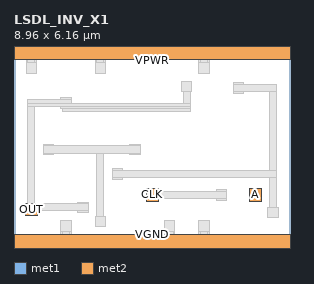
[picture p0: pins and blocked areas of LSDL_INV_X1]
MACRO LSDL_INV_X1
 CLASS CORE ;
 FOREIGN LSDL_INV_X1 0 0 ;
 SIZE 8.96 BY 6.16 ;
 ORIGIN 0 0 ;
 SYMMETRY X Y R90 ;
 SITE unit ;
  PIN VPWR
   DIRECTION INOUT ;
   USE POWER ;
   SHAPE ABUTMENT ;
    PORT
     CLASS CORE ;
       LAYER met1 ;
        RECT 0.00000000 5.92000000 8.96000000 6.40000000 ;
       LAYER met2 ;
        RECT 0.00000000 5.92000000 8.96000000 6.40000000 ;
    END
  END VPWR

  PIN VGND
   DIRECTION INOUT ;
   USE POWER ;
   SHAPE ABUTMENT ;
    PORT
     CLASS CORE ;
       LAYER met1 ;
        RECT 0.00000000 -0.24000000 8.96000000 0.24000000 ;
       LAYER met2 ;
        RECT 0.00000000 -0.24000000 8.96000000 0.24000000 ;
    END
  END VGND

  PIN OUT
   DIRECTION INOUT ;
   USE SIGNAL ;
   SHAPE ABUTMENT ;
    PORT
     CLASS CORE ;
       LAYER met2 ;
        RECT 0.36000000 0.86000000 0.76000000 1.26000000 ;
    END
  END OUT

  PIN CLK
   DIRECTION INOUT ;
   USE SIGNAL ;
   SHAPE ABUTMENT ;
    PORT
     CLASS CORE ;
       LAYER met2 ;
        RECT 4.28000000 1.32700000 4.68000000 1.72700000 ;
    END
  END CLK

  PIN A
   DIRECTION INOUT ;
   USE SIGNAL ;
   SHAPE ABUTMENT ;
    PORT
     CLASS CORE ;
       LAYER met2 ;
        RECT 7.64000000 1.32700000 8.04000000 1.72700000 ;
    END
  END A

 OBS
    LAYER polycont ;
     RECT 4.37000000 1.41700000 4.59000000 1.63700000 ;
     RECT 6.61000000 1.41700000 6.83000000 1.63700000 ;
     RECT 2.13000000 1.01200000 2.35000000 1.23200000 ;
     RECT 5.49000000 4.92700000 5.71000000 5.14700000 ;
     RECT 3.25000000 2.09200000 3.47000000 2.31200000 ;
     RECT 7.73000000 1.41700000 7.95000000 1.63700000 ;
     RECT 1.01000000 2.89000000 1.23000000 3.11000000 ;

    LAYER pdiffc ;
     RECT 1.57000000 4.39000000 1.79000000 4.61000000 ;
     RECT 0.45000000 5.53000000 0.67000000 5.75000000 ;
     RECT 2.69000000 5.53000000 2.91000000 5.75000000 ;
     RECT 6.05000000 5.53000000 6.27000000 5.75000000 ;
     RECT 7.17000000 4.89000000 7.39000000 5.11000000 ;
     RECT 3.81000000 2.89000000 4.03000000 3.11000000 ;

    LAYER ndiffc ;
     RECT 0.45000000 0.95000000 0.67000000 1.17000000 ;
     RECT 8.29000000 0.85000000 8.51000000 1.07000000 ;
     RECT 1.57000000 0.41000000 1.79000000 0.63000000 ;
     RECT 4.93000000 0.41000000 5.15000000 0.63000000 ;
     RECT 6.05000000 0.41000000 6.27000000 0.63000000 ;
     RECT 2.69000000 0.55000000 2.91000000 0.77000000 ;

    LAYER met1 ;
     RECT 1.51000000 0.24000000 1.56500000 0.35000000 ;
     RECT 1.79500000 0.24000000 1.85000000 0.35000000 ;
     RECT 4.87000000 0.24000000 4.92500000 0.35000000 ;
     RECT 5.15500000 0.24000000 5.21000000 0.35000000 ;
     RECT 5.99000000 0.24000000 6.04500000 0.35000000 ;
     RECT 6.27500000 0.24000000 6.33000000 0.35000000 ;
     RECT 0.39000000 5.81000000 0.44500000 5.92000000 ;
     RECT 0.67500000 5.81000000 0.73000000 5.92000000 ;
     RECT 2.63000000 5.81000000 2.68500000 5.92000000 ;
     RECT 2.91500000 5.81000000 2.97000000 5.92000000 ;
     RECT 5.99000000 5.81000000 6.04500000 5.92000000 ;
     RECT 6.27500000 5.81000000 6.33000000 5.92000000 ;
     RECT 4.28000000 1.32700000 4.68000000 1.41200000 ;
     RECT 6.55000000 1.35700000 6.89000000 1.41200000 ;
     RECT 4.28000000 1.41200000 6.89000000 1.64200000 ;
     RECT 6.55000000 1.64200000 6.89000000 1.69700000 ;
     RECT 4.28000000 1.64200000 4.68000000 1.72700000 ;
     RECT 0.36000000 0.86000000 0.76000000 1.00700000 ;
     RECT 2.07000000 0.95200000 2.41000000 1.00700000 ;
     RECT 0.36000000 1.00700000 2.41000000 1.23700000 ;
     RECT 0.36000000 1.23700000 0.76000000 1.26000000 ;
     RECT 2.07000000 1.23700000 2.41000000 1.29200000 ;
     RECT 1.56500000 4.24700000 5.71500000 4.33000000 ;
     RECT 0.44500000 1.26000000 0.67500000 4.38500000 ;
     RECT 1.51000000 4.33000000 5.71500000 4.38500000 ;
     RECT 0.44500000 4.38500000 5.71500000 4.47700000 ;
     RECT 0.44500000 4.47700000 1.85000000 4.61500000 ;
     RECT 1.51000000 4.61500000 1.85000000 4.67000000 ;
     RECT 5.48500000 4.47700000 5.71500000 4.86700000 ;
     RECT 5.43000000 4.86700000 5.77000000 5.20700000 ;
     RECT 0.39000000 5.47000000 0.73000000 5.81000000 ;
     RECT 2.63000000 5.47000000 2.97000000 5.81000000 ;
     RECT 5.99000000 5.47000000 6.33000000 5.81000000 ;
     RECT 0.44500000 5.81000000 0.67500000 5.92000000 ;
     RECT 2.68500000 5.81000000 2.91500000 5.92000000 ;
     RECT 6.04500000 5.81000000 6.27500000 5.92000000 ;
     RECT 0.00000000 5.92000000 8.96000000 6.40000000 ;
     RECT 8.23000000 0.79000000 8.57000000 1.13000000 ;
     RECT 3.19000000 2.03200000 3.53000000 2.08700000 ;
     RECT 8.28500000 1.13000000 8.51500000 2.08700000 ;
     RECT 3.19000000 2.08700000 8.51500000 2.31700000 ;
     RECT 3.19000000 2.31700000 3.53000000 2.37200000 ;
     RECT 7.11000000 4.83000000 7.45000000 4.88500000 ;
     RECT 8.28500000 2.31700000 8.51500000 4.88500000 ;
     RECT 7.11000000 4.88500000 8.51500000 5.11500000 ;
     RECT 7.11000000 5.11500000 7.45000000 5.17000000 ;
     RECT 0.00000000 -0.24000000 8.96000000 0.24000000 ;
     RECT 1.56500000 0.24000000 1.79500000 0.35000000 ;
     RECT 4.92500000 0.24000000 5.15500000 0.35000000 ;
     RECT 6.04500000 0.24000000 6.27500000 0.35000000 ;
     RECT 1.51000000 0.35000000 1.85000000 0.69000000 ;
     RECT 4.87000000 0.35000000 5.21000000 0.69000000 ;
     RECT 5.99000000 0.35000000 6.33000000 0.69000000 ;
     RECT 7.64000000 1.32700000 8.04000000 1.72700000 ;
     RECT 2.63000000 0.49000000 2.97000000 0.83000000 ;
     RECT 0.95000000 2.83000000 1.29000000 2.88500000 ;
     RECT 2.68500000 0.83000000 2.91500000 2.88500000 ;
     RECT 3.75000000 2.83000000 4.09000000 2.88500000 ;
     RECT 0.95000000 2.88500000 4.09000000 3.11500000 ;
     RECT 0.95000000 3.11500000 1.29000000 3.17000000 ;
     RECT 3.75000000 3.11500000 4.09000000 3.17000000 ;

    LAYER via1 ;
     RECT 4.35000000 1.39700000 4.61000000 1.65700000 ;
     RECT 0.43000000 0.93000000 0.69000000 1.19000000 ;
     RECT 0.43000000 6.03000000 0.69000000 6.29000000 ;
     RECT 1.55000000 6.03000000 1.81000000 6.29000000 ;
     RECT 2.67000000 6.03000000 2.93000000 6.29000000 ;
     RECT 3.79000000 6.03000000 4.05000000 6.29000000 ;
     RECT 4.91000000 6.03000000 5.17000000 6.29000000 ;
     RECT 6.03000000 6.03000000 6.29000000 6.29000000 ;
     RECT 7.15000000 6.03000000 7.41000000 6.29000000 ;
     RECT 8.27000000 6.03000000 8.53000000 6.29000000 ;
     RECT 0.43000000 -0.13000000 0.69000000 0.13000000 ;
     RECT 1.55000000 -0.13000000 1.81000000 0.13000000 ;
     RECT 2.67000000 -0.13000000 2.93000000 0.13000000 ;
     RECT 3.79000000 -0.13000000 4.05000000 0.13000000 ;
     RECT 4.91000000 -0.13000000 5.17000000 0.13000000 ;
     RECT 6.03000000 -0.13000000 6.29000000 0.13000000 ;
     RECT 7.15000000 -0.13000000 7.41000000 0.13000000 ;
     RECT 8.27000000 -0.13000000 8.53000000 0.13000000 ;
     RECT 7.71000000 1.39700000 7.97000000 1.65700000 ;

    LAYER met2 ;
     RECT 4.28000000 1.32700000 4.68000000 1.72700000 ;
     RECT 0.36000000 0.86000000 0.76000000 1.26000000 ;
     RECT 0.00000000 5.92000000 8.96000000 6.40000000 ;
     RECT 0.00000000 -0.24000000 8.96000000 0.24000000 ;
     RECT 7.64000000 1.32700000 8.04000000 1.72700000 ;

 END
END LSDL_INV_X1
